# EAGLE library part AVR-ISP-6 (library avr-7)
AVR ISP-6 Serial Programming Header

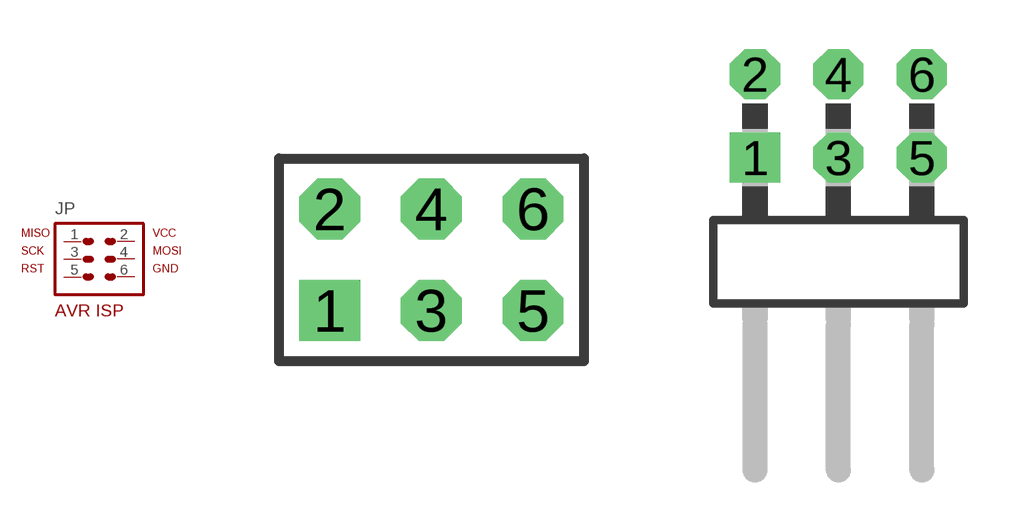
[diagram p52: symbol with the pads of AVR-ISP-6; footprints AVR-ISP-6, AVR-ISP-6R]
Designator prefix JP

## AVR-ISP-6VERT  [AVR-ISP-6]
1  1  pas
2  2  pas
3  3  pas
4  4  pas
5  5  pas
6  6  pas

## AVR-ISP-6HORZ  [AVR-ISP-6R]
Pads as for AVR-ISP-6

## Footprint AVR-ISP-6 (pad centres in mm)
PIN HEADER JTAG 6 Pin, 0.1" Straight
drill 1.016 square: 1 -2.54,-1.27
drill 1.016 octagon: 2 -2.54,1.27; 3 0,-1.27; 4 0,1.27; 5 2.54,-1.27; 6 2.54,1.27

## Footprint AVR-ISP-6R (pad centres in mm)
PIN HEADER AVR ISP 6 Pin, 0.1" Right Angle
drill 1.016 square: 1 -2.54,-1.27
drill 1.016 octagon: 2 -2.54,1.27; 3 0,-1.27; 4 0,1.27; 5 2.54,-1.27; 6 2.54,1.27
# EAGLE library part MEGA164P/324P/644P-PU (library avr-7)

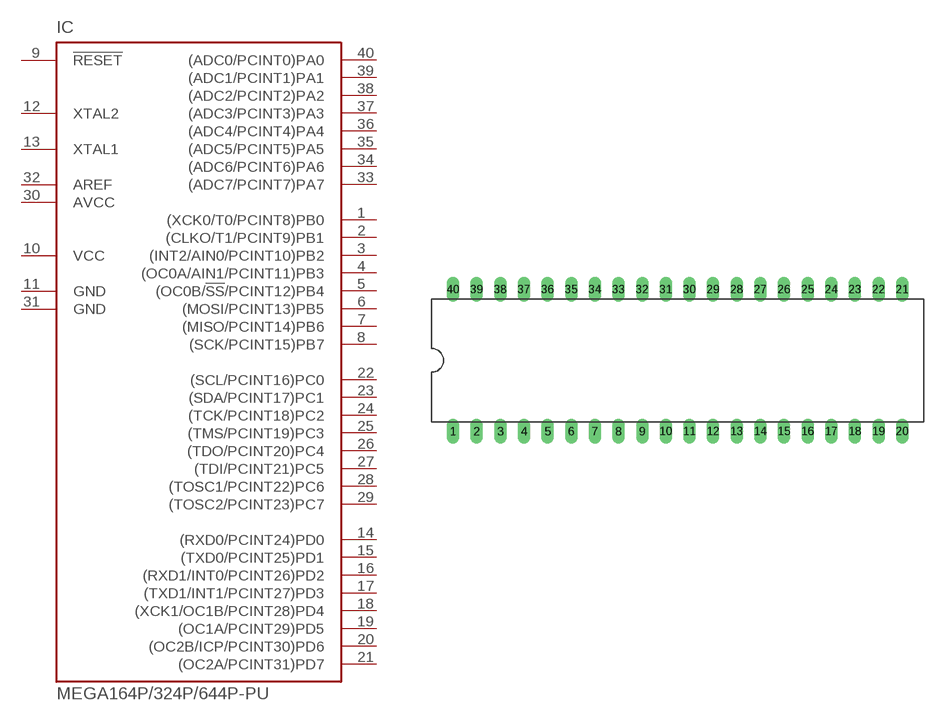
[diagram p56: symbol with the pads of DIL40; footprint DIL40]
Designator prefix IC

## MEGA164P/324P/644P-PU  [DIL40]
1  (XCK0/T0/PCINT8)PB0
2  (CLKO/T1/PCINT9)PB1
3  (INT2/AIN0/PCINT10)PB2
4  (OC0A/AIN1/PCINT11)PB3
5  (OC0B/!SS!/PCINT12)PB4
6  (MOSI/PCINT13)PB5
7  (MISO/PCINT14)PB6
8  (SCK/PCINT15)PB7
9  !RESET  in
10  VCC  pwr
11  GND  pwr
12  XTAL2  out
13  XTAL1  in
14  (RXD0/PCINT24)PD0
15  (TXD0/PCINT25)PD1
16  (RXD1/INT0/PCINT26)PD2
17  (TXD1/INT1/PCINT27)PD3
18  (XCK1/OC1B/PCINT28)PD4
19  (OC1A/PCINT29)PD5
20  (OC2B/ICP/PCINT30)PD6
21  (OC2A/PCINT31)PD7
22  (SCL/PCINT16)PC0
23  (SDA/PCINT17)PC1
24  (TCK/PCINT18)PC2
25  (TMS/PCINT19)PC3
26  (TDO/PCINT20)PC4
27  (TDI/PCINT21)PC5
28  (TOSC1/PCINT22)PC6
29  (TOSC2/PCINT23)PC7
30  AVCC  pwr
31  GND  pwr
32  AREF  pwr
33  (ADC7/PCINT7)PA7
34  (ADC6/PCINT6)PA6
35  (ADC5/PCINT5)PA5
36  (ADC4/PCINT4)PA4
37  (ADC3/PCINT3)PA3
38  (ADC2/PCINT2)PA2
39  (ADC1/PCINT1)PA1
40  (ADC0/PCINT0)PA0

## Footprint DIL40 (pad centres in mm)
Dual In Line
drill 0.813 long: 1 -24.13,-7.62; 2 -21.59,-7.62; 3 -19.05,-7.62; 4 -16.51,-7.62; 5 -13.97,-7.62; 6 -11.43,-7.62; 7 -8.89,-7.62; 8 -6.35,-7.62; 9 -3.81,-7.62; 10 -1.27,-7.62; 11 1.27,-7.62; 12 3.81,-7.62; 13 6.35,-7.62; 14 8.89,-7.62; 15 11.43,-7.62; 16 13.97,-7.62; 17 16.51,-7.62; 18 19.05,-7.62; 19 21.59,-7.62; 20 24.13,-7.62; 21 24.13,7.62; 22 21.59,7.62; 23 19.05,7.62; 24 16.51,7.62; 25 13.97,7.62; 26 11.43,7.62; 27 8.89,7.62; 28 6.35,7.62; 29 3.81,7.62; 30 1.27,7.62; 31 -1.27,7.62; 32 -3.81,7.62; 33 -6.35,7.62; 34 -8.89,7.62; 35 -11.43,7.62; 36 -13.97,7.62; 37 -16.51,7.62; 38 -19.05,7.62; 39 -21.59,7.62; 40 -24.13,7.62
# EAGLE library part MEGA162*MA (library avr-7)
Atmel Mega162 TQFP and MLF packages

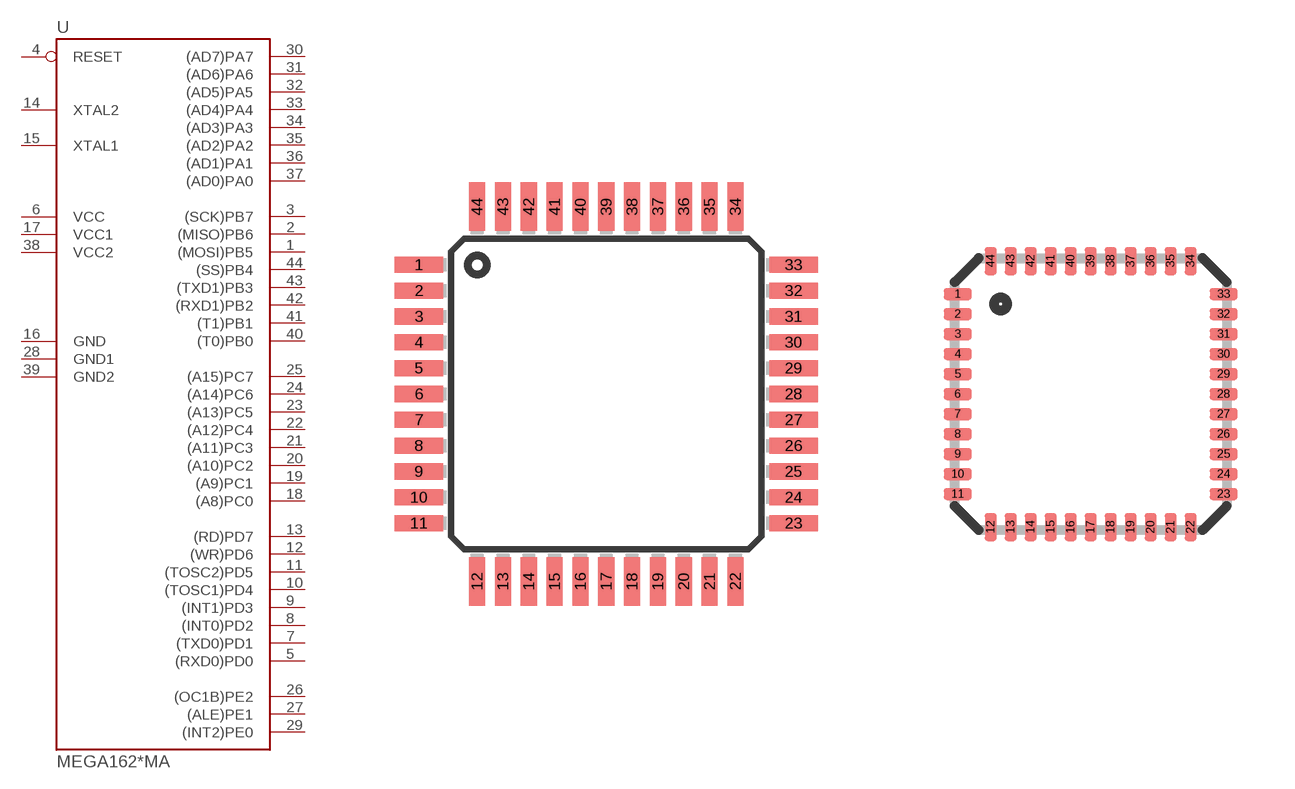
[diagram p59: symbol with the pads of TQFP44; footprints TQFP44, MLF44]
Designator prefix -

## MEGA162MA*A*  [TQFP44]
1  (MOSI)PB5
2  (MISO)PB6
3  (SCK)PB7
4  RESET  in
5  (RXD0)PD0
6  VCC  pwr
7  (TXD0)PD1
8  (INT0)PD2
9  (INT1)PD3
10  (TOSC1)PD4
11  (TOSC2)PD5
12  (WR)PD6
13  (RD)PD7
14  XTAL2  in
15  XTAL1  in
16  GND  pwr
17  VCC1  pwr
18  (A8)PC0
19  (A9)PC1
20  (A10)PC2
21  (A11)PC3
22  (A12)PC4
23  (A13)PC5
24  (A14)PC6
25  (A15)PC7
26  (OC1B)PE2
27  (ALE)PE1
28  GND1  pwr
29  (INT2)PE0
30  (AD7)PA7
31  (AD6)PA6
32  (AD5)PA5
33  (AD4)PA4
34  (AD3)PA3
35  (AD2)PA2
36  (AD1)PA1
37  (AD0)PA0
38  VCC2  pwr
39  GND2  pwr
40  (T0)PB0
41  (T1)PB1
42  (RXD1)PB2
43  (TXD1)PB3
44  (SS)PB4

## MEGA162MA*M*  [MLF44]
Pads as for TQFP44

## Footprint TQFP44 (pad centres in mm)
Thin Plasic Quad Flat Package
smd 1.5 x 0.5: 1 -5.8,4; 2 -5.8,3.2; 3 -5.8,2.4; 4 -5.8,1.6; 5 -5.8,0.8; 6 -5.8,0; 7 -5.8,-0.8; 8 -5.8,-1.6; 9 -5.8,-2.4; 10 -5.8,-3.2; 11 -5.8,-4; 23 5.8,-4; 24 5.8,-3.2; 25 5.8,-2.4; 26 5.8,-1.6; 27 5.8,-0.8; 28 5.8,0; 29 5.8,0.8; 30 5.8,1.6; 31 5.8,2.4; 32 5.8,3.2; 33 5.8,4
smd 0.5 x 1.5: 12 -4,-5.8; 13 -3.2,-5.8; 14 -2.4,-5.8; 15 -1.6,-5.8; 16 -0.8,-5.8; 17 0,-5.8; 18 0.8,-5.8; 19 1.6,-5.8; 20 2.4,-5.8; 21 3.2,-5.8; 22 4,-5.8; 34 4,5.8; 35 3.2,5.8; 36 2.4,5.8; 37 1.6,5.8; 38 0.8,5.8; 39 0,5.8; 40 -0.8,5.8; 41 -1.6,5.8; 42 -2.4,5.8; 43 -3.2,5.8; 44 -4,5.8

## Footprint MLF44 (pad centres in mm)
44M1 Micro Lead Frame package (MLF)
smd 0.7 x 0.3: 1 -3.325,2.5; 2 -3.325,2; 3 -3.325,1.5; 4 -3.325,1; 5 -3.325,0.5; 6 -3.325,0; 7 -3.325,-0.5; 8 -3.325,-1; 9 -3.325,-1.5; 10 -3.325,-2; 11 -3.325,-2.5; 23 3.325,-2.5; 24 3.325,-2; 25 3.325,-1.5; 26 3.325,-1; 27 3.325,-0.5; 28 3.325,0; 29 3.325,0.5; 30 3.325,1; 31 3.325,1.5; 32 3.325,2; 33 3.325,2.5
smd 0.3 x 0.7: 12 -2.5,-3.325; 13 -2,-3.325; 14 -1.5,-3.325; 15 -1,-3.325; 16 -0.5,-3.325; 17 0,-3.325; 18 0.5,-3.325; 19 1,-3.325; 20 1.5,-3.325; 21 2,-3.325; 22 2.5,-3.325; 34 2.5,3.325; 35 2,3.325; 36 1.5,3.325; 37 1,3.325; 38 0.5,3.325; 39 0,3.325; 40 -0.5,3.325; 41 -1,3.325; 42 -1.5,3.325; 43 -2,3.325; 44 -2.5,3.325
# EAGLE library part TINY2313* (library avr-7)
Atmel Tiny2313 2K Flash, 128 bytes EEPROM, 128 bytes RAM

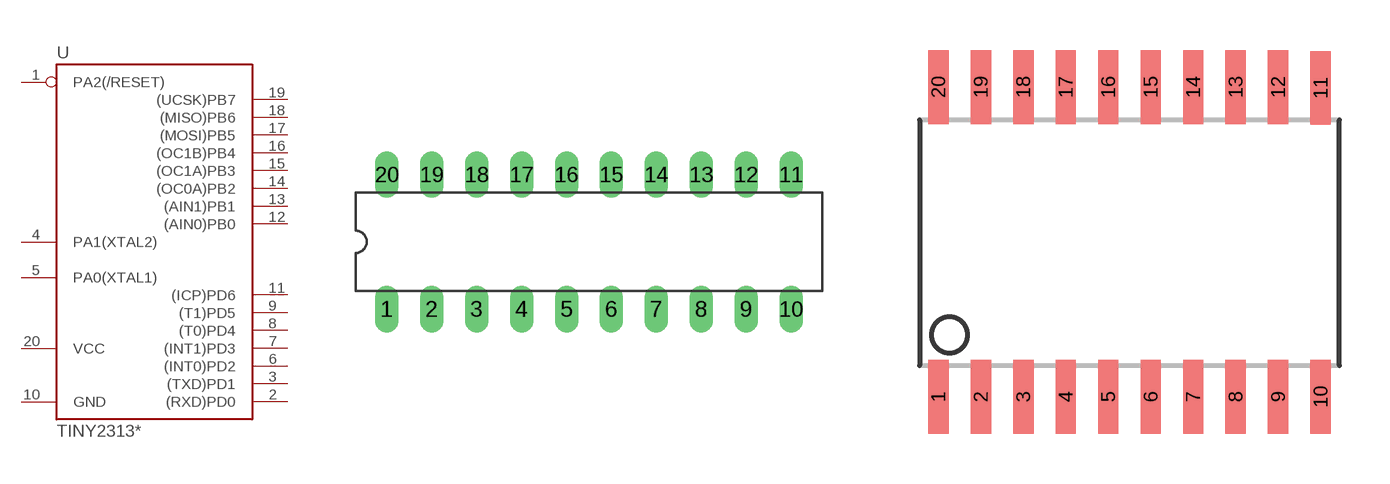
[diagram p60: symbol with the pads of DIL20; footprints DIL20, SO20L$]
Designator prefix -

## TINY2313-*P*  [DIL20]
1  PA2(/RESET)  in
2  (RXD)PD0
3  (TXD)PD1
4  PA1(XTAL2)
5  PA0(XTAL1)
6  (INT0)PD2
7  (INT1)PD3
8  (T0)PD4
9  (T1)PD5
10  GND  pwr
11  (ICP)PD6
12  (AIN0)PB0
13  (AIN1)PB1
14  (OC0A)PB2
15  (OC1A)PB3
16  (OC1B)PB4
17  (MOSI)PB5
18  (MISO)PB6
19  (UCSK)PB7
20  VCC  pwr

## TINY2313-*S*  [SO20L$]
Pads as for DIL20

## TINY2313-*M*  [MLF20]
P$1  (TXD)PD1
P$2  PA1(XTAL2)
P$3  PA0(XTAL1)
P$4  (INT0)PD2
P$5  (INT1)PD3
P$6  (T0)PD4
P$7  (T1)PD5
P$8  GND  pwr
P$9  (ICP)PD6
P$10  (AIN0)PB0
P$11  (AIN1)PB1
P$12  (OC0A)PB2
P$13  (OC1A)PB3
P$14  (OC1B)PB4
P$15  (MOSI)PB5
P$16  (MISO)PB6
P$17  (UCSK)PB7
P$18  VCC  pwr
P$19  PA2(/RESET)  in
P$20  (RXD)PD0

## Footprint DIL20 (pad centres in mm)
Dual In Line
drill 0.813 long: 1 -11.43,-3.81; 2 -8.89,-3.81; 3 -6.35,-3.81; 4 -3.81,-3.81; 5 -1.27,-3.81; 6 1.27,-3.81; 7 3.81,-3.81; 8 6.35,-3.81; 9 8.89,-3.81; 10 11.43,-3.81; 11 11.43,3.81; 12 8.89,3.81; 13 6.35,3.81; 14 3.81,3.81; 15 1.27,3.81; 16 -1.27,3.81; 17 -3.81,3.81; 18 -6.35,3.81; 19 -8.89,3.81; 20 -11.43,3.81

## Footprint SO20L$ (pad centres in mm)
Small Outline Package, large
smd 0.61 x 2.21: 1 -5.715,-4.636; 2 -4.445,-4.636; 3 -3.175,-4.636; 4 -1.905,-4.636; 5 -0.635,-4.636; 6 0.635,-4.636; 7 1.905,-4.636; 8 3.175,-4.636; 9 4.445,-4.636; 10 5.715,-4.636; 11 5.715,4.61; 12 4.445,4.636; 13 3.175,4.636; 14 1.905,4.636; 15 0.635,4.636; 16 -0.635,4.636; 17 -1.905,4.636; 18 -3.175,4.636; 19 -4.445,4.636; 20 -5.715,4.636

## Footprint MLF20 (pad centres in mm)
HP-VFQFP-N20 Micro Lead Frame package (MLF)
smd 0.8 x 0.23: P$1 -2,1; P$2 -2,0.5; P$3 -2,0; P$4 -2,-0.5; P$5 -2,-1; P$11 2,-1; P$12 2,-0.5; P$13 2,0; P$14 2,0.5; P$15 2,1
smd 0.23 x 0.8: P$6 -1,-2; P$7 -0.5,-2; P$8 0,-2; P$9 0.5,-2; P$10 1,-2; P$16 1,2; P$17 0.5,2; P$18 0,2; P$19 -0.5,2; P$20 -1,2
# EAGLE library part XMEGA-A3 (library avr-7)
Atmel XMega A3 series processor

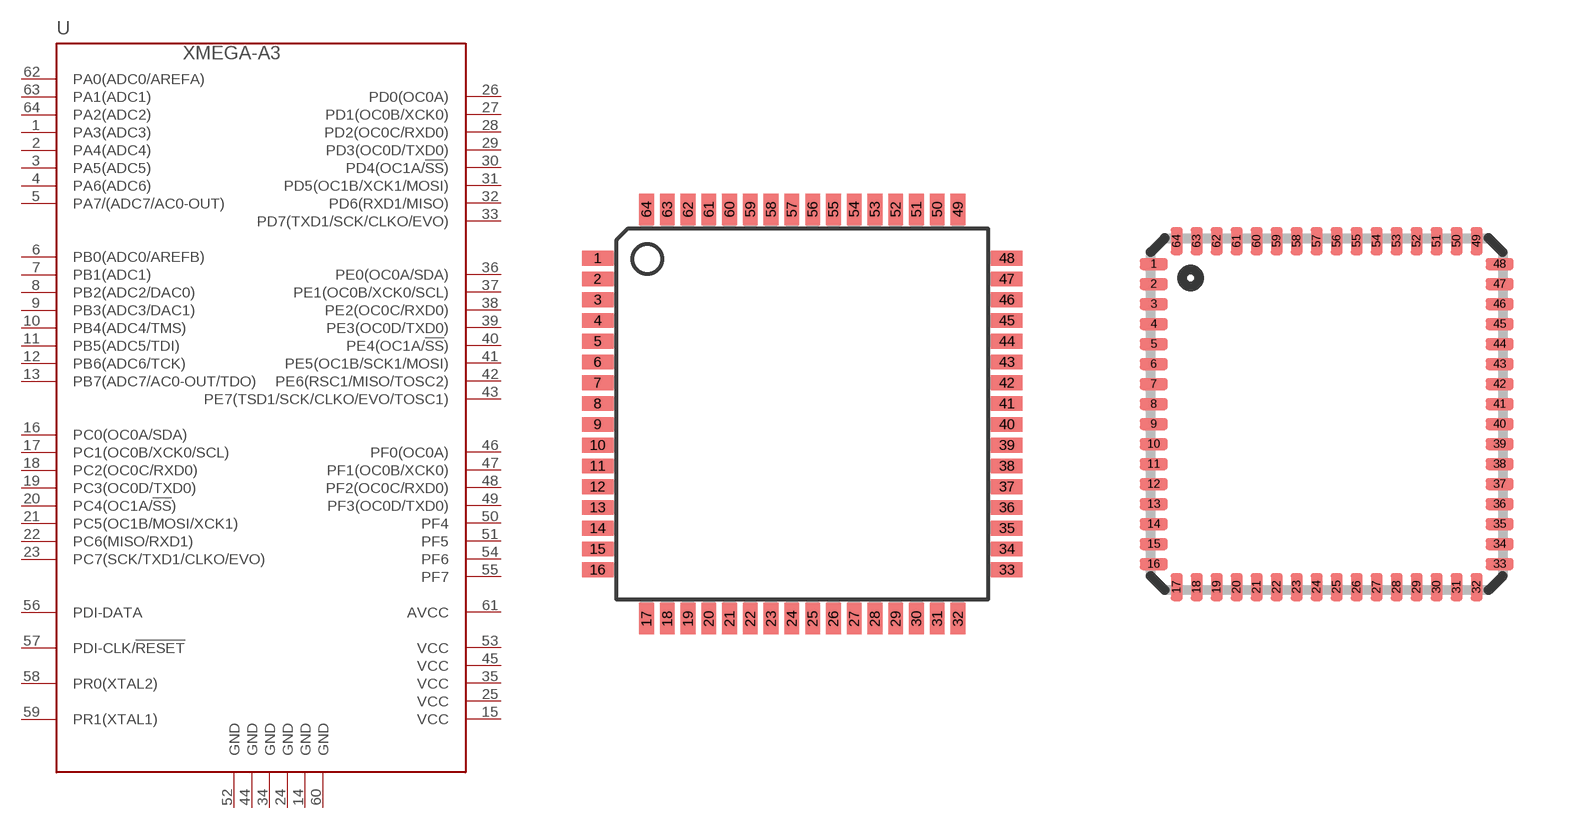
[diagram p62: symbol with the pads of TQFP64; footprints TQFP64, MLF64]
Designator prefix -

## XMEGA-A3TQFP  [TQFP64]
1  PA3(ADC3)
2  PA4(ADC4)
3  PA5(ADC5)
4  PA6(ADC6)
5  PA7/(ADC7/AC0-OUT)
6  PB0(ADC0/AREFB)
7  PB1(ADC1)
8  PB2(ADC2/DAC0)
9  PB3(ADC3/DAC1)
10  PB4(ADC4/TMS)
11  PB5(ADC5/TDI)
12  PB6(ADC6/TCK)
13  PB7(ADC7/AC0-OUT/TDO)
14  GND  pwr
15  VCC  pwr
16  PC0(OC0A/SDA)
17  PC1(OC0B/XCK0/SCL)
18  PC2(OC0C/RXD0)
19  PC3(OC0D/TXD0)
20  PC4(OC1A/!SS!)
21  PC5(OC1B/MOSI/XCK1)
22  PC6(MISO/RXD1)
23  PC7(SCK/TXD1/CLKO/EVO)
24  GND  pwr
25  VCC  pwr
26  PD0(OC0A)
27  PD1(OC0B/XCK0)
28  PD2(OC0C/RXD0)
29  PD3(OC0D/TXD0)
30  PD4(OC1A/!SS!)
31  PD5(OC1B/XCK1/MOSI)
32  PD6(RXD1/MISO)
33  PD7(TXD1/SCK/CLKO/EVO)
34  GND  pwr
35  VCC  pwr
36  PE0(OC0A/SDA)
37  PE1(OC0B/XCK0/SCL)
38  PE2(OC0C/RXD0)
39  PE3(OC0D/TXD0)
40  PE4(OC1A/!SS!)
41  PE5(OC1B/SCK1/MOSI)
42  PE6(RSC1/MISO/TOSC2)
43  PE7(TSD1/SCK/CLKO/EVO/TOSC1)
44  GND  pwr
45  VCC  pwr
46  PF0(OC0A)
47  PF1(OC0B/XCK0)
48  PF2(OC0C/RXD0)
49  PF3(OC0D/TXD0)
50  PF4
51  PF5
52  GND  pwr
53  VCC  pwr
54  PF6
55  PF7
56  PDI-DATA
57  PDI-CLK/!RESET  in
58  PR0(XTAL2)
59  PR1(XTAL1)
60  GND  pwr
61  AVCC  pwr
62  PA0(ADC0/AREFA)
63  PA1(ADC1)
64  PA2(ADC2)

## XMEGA-A3MLF  [MLF64]
Pads as for TQFP64

## Footprint TQFP64 (pad centres in mm)
Thin Plasic Quad Flat Package
smd 1.194 x 0.559: 1 -7.76,5.905; 2 -7.76,5.118; 3 -7.76,4.331; 4 -7.76,3.543; 5 -7.76,2.756; 6 -7.76,1.968; 7 -7.76,1.181; 8 -7.76,0.394; 9 -7.76,-0.394; 10 -7.76,-1.181; 11 -7.76,-1.968; 12 -7.76,-2.756; 13 -7.76,-3.543; 14 -7.76,-4.331; 15 -7.76,-5.118; 16 -7.76,-5.905; 33 7.76,-5.905; 34 7.76,-5.118; 35 7.76,-4.331; 36 7.76,-3.543; 37 7.76,-2.756; 38 7.76,-1.968; 39 7.76,-1.181; 40 7.76,-0.394; 41 7.76,0.394; 42 7.76,1.181; 43 7.76,1.968; 44 7.76,2.756; 45 7.76,3.543; 46 7.76,4.331; 47 7.76,5.118; 48 7.76,5.905
smd 0.559 x 1.194: 17 -5.905,-7.76; 18 -5.118,-7.76; 19 -4.331,-7.76; 20 -3.543,-7.76; 21 -2.756,-7.76; 22 -1.968,-7.76; 23 -1.181,-7.76; 24 -0.394,-7.76; 25 0.394,-7.76; 26 1.181,-7.76; 27 1.968,-7.76; 28 2.756,-7.76; 29 3.543,-7.76; 30 4.331,-7.76; 31 5.118,-7.76; 32 5.905,-7.76; 49 5.905,7.76; 50 5.118,7.76; 51 4.331,7.76; 52 3.543,7.76; 53 2.756,7.76; 54 1.968,7.76; 55 1.181,7.76; 56 0.394,7.76; 57 -0.394,7.76; 58 -1.181,7.76; 59 -1.968,7.76; 60 -2.756,7.76; 61 -3.543,7.76; 62 -4.331,7.76; 63 -5.118,7.76; 64 -5.905,7.76

## Footprint MLF64 (pad centres in mm)
64M1 Micro Lead Frame package (MLF)
smd 0.7 x 0.3: 1 -4.325,3.75; 2 -4.325,3.25; 3 -4.325,2.75; 4 -4.325,2.25; 5 -4.325,1.75; 6 -4.325,1.25; 7 -4.325,0.75; 8 -4.325,0.25; 9 -4.325,-0.25; 10 -4.325,-0.75; 11 -4.325,-1.25; 12 -4.325,-1.75; 13 -4.325,-2.25; 14 -4.325,-2.75; 15 -4.325,-3.25; 16 -4.325,-3.75; 33 4.325,-3.75; 34 4.325,-3.25; 35 4.325,-2.75; 36 4.325,-2.25; 37 4.325,-1.75; 38 4.325,-1.25; 39 4.325,-0.75; 40 4.325,-0.25; 41 4.325,0.25; 42 4.325,0.75; 43 4.325,1.25; 44 4.325,1.75; 45 4.325,2.25; 46 4.325,2.75; 47 4.325,3.25; 48 4.325,3.75
smd 0.3 x 0.7: 17 -3.75,-4.325; 18 -3.25,-4.325; 19 -2.75,-4.325; 20 -2.25,-4.325; 21 -1.75,-4.325; 22 -1.25,-4.325; 23 -0.75,-4.325; 24 -0.25,-4.325; 25 0.25,-4.325; 26 0.75,-4.325; 27 1.25,-4.325; 28 1.75,-4.325; 29 2.25,-4.325; 30 2.75,-4.325; 31 3.25,-4.325; 32 3.75,-4.325; 49 3.75,4.325; 50 3.25,4.325; 51 2.75,4.325; 52 2.25,4.325; 53 1.75,4.325; 54 1.25,4.325; 55 0.75,4.325; 56 0.25,4.325; 57 -0.25,4.325; 58 -0.75,4.325; 59 -1.25,4.325; 60 -1.75,4.325; 61 -2.25,4.325; 62 -2.75,4.325; 63 -3.25,4.325; 64 -3.75,4.325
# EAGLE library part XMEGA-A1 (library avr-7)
Atmel XMega A1 Series processor

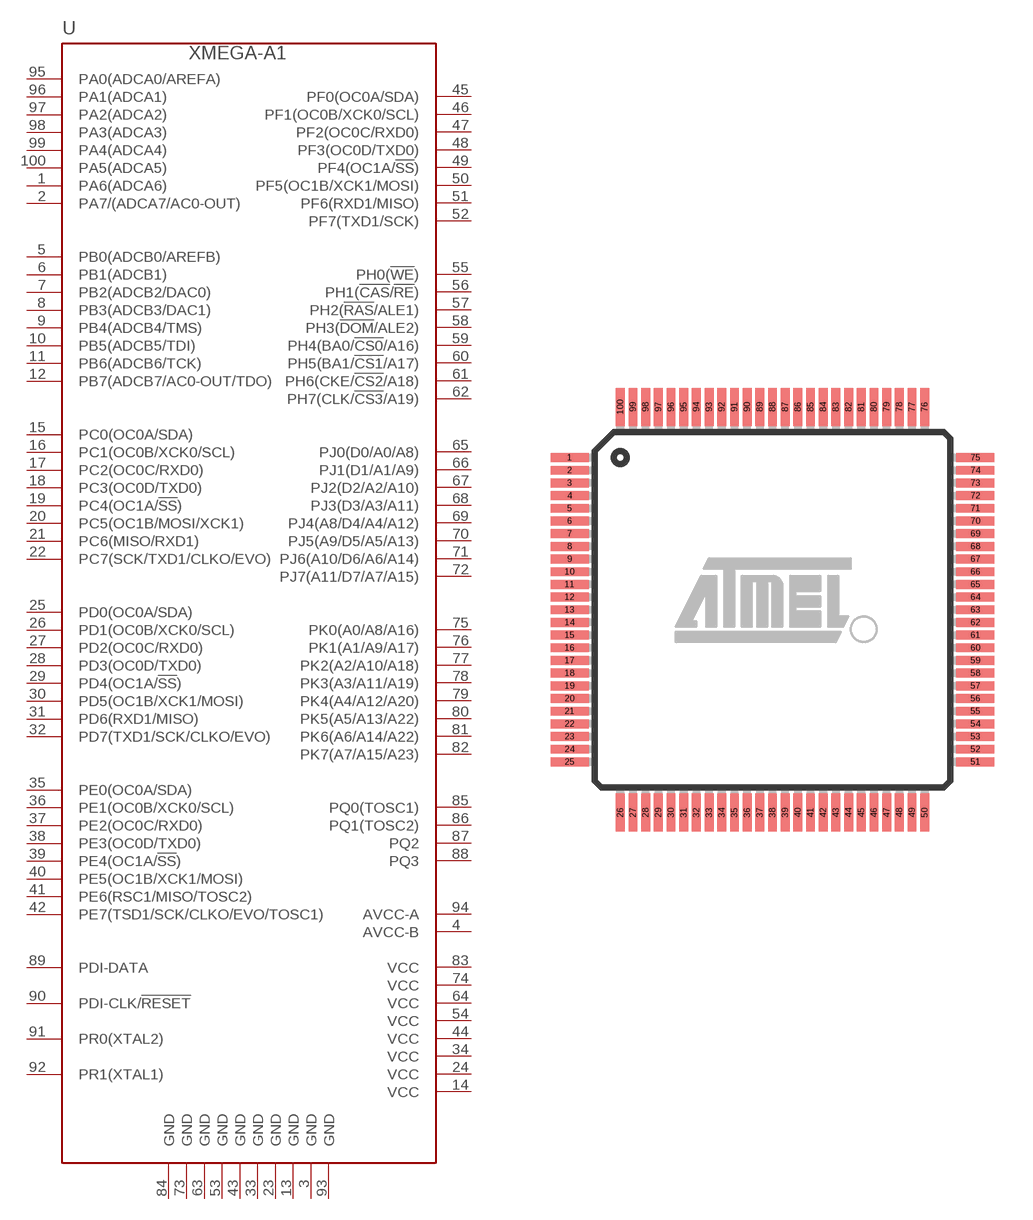
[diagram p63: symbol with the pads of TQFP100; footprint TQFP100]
Designator prefix -

## XMEGA-A1TQFP  [TQFP100]
1  PA6(ADCA6)
2  PA7/(ADCA7/AC0-OUT)
3  GND  pwr
4  AVCC-B  pwr
5  PB0(ADCB0/AREFB)
6  PB1(ADCB1)
7  PB2(ADCB2/DAC0)
8  PB3(ADCB3/DAC1)
9  PB4(ADCB4/TMS)
10  PB5(ADCB5/TDI)
11  PB6(ADCB6/TCK)
12  PB7(ADCB7/AC0-OUT/TDO)
13  GND  pwr
14  VCC  pwr
15  PC0(OC0A/SDA)
16  PC1(OC0B/XCK0/SCL)
17  PC2(OC0C/RXD0)
18  PC3(OC0D/TXD0)
19  PC4(OC1A/!SS!)
20  PC5(OC1B/MOSI/XCK1)
21  PC6(MISO/RXD1)
22  PC7(SCK/TXD1/CLKO/EVO)
23  GND  pwr
24  VCC  pwr
25  PD0(OC0A/SDA)
26  PD1(OC0B/XCK0/SCL)
27  PD2(OC0C/RXD0)
28  PD3(OC0D/TXD0)
29  PD4(OC1A/!SS!)
30  PD5(OC1B/XCK1/MOSI)
31  PD6(RXD1/MISO)
32  PD7(TXD1/SCK/CLKO/EVO)
33  GND  pwr
34  VCC  pwr
35  PE0(OC0A/SDA)
36  PE1(OC0B/XCK0/SCL)
37  PE2(OC0C/RXD0)
38  PE3(OC0D/TXD0)
39  PE4(OC1A/!SS!)
40  PE5(OC1B/XCK1/MOSI)
41  PE6(RSC1/MISO/TOSC2)
42  PE7(TSD1/SCK/CLKO/EVO/TOSC1)
43  GND  pwr
44  VCC  pwr
45  PF0(OC0A/SDA)
46  PF1(OC0B/XCK0/SCL)
47  PF2(OC0C/RXD0)
48  PF3(OC0D/TXD0)
49  PF4(OC1A/!SS!)
50  PF5(OC1B/XCK1/MOSI)
51  PF6(RXD1/MISO)
52  PF7(TXD1/SCK)
53  GND  pwr
54  VCC  pwr
55  PH0(!WE!)
56  PH1(!CAS!/!RE!)
57  PH2(!RAS!/ALE1)
58  PH3(!DOM!/ALE2)
59  PH4(BA0/!CS0!/A16)
60  PH5(BA1/!CS1!/A17)
61  PH6(CKE/!CS2!/A18)
62  PH7(CLK/!CS3!/A19)
63  GND  pwr
64  VCC  pwr
65  PJ0(D0/A0/A8)
66  PJ1(D1/A1/A9)
67  PJ2(D2/A2/A10)
68  PJ3(D3/A3/A11)
69  PJ4(A8/D4/A4/A12)
70  PJ5(A9/D5/A5/A13)
71  PJ6(A10/D6/A6/A14)
72  PJ7(A11/D7/A7/A15)
73  GND  pwr
74  VCC  pwr
75  PK0(A0/A8/A16)
76  PK1(A1/A9/A17)
77  PK2(A2/A10/A18)
78  PK3(A3/A11/A19)
79  PK4(A4/A12/A20)
80  PK5(A5/A13/A22)
81  PK6(A6/A14/A22)
82  PK7(A7/A15/A23)
83  VCC  pwr
84  GND  pwr
85  PQ0(TOSC1)
86  PQ1(TOSC2)
87  PQ2
88  PQ3
89  PDI-DATA
90  PDI-CLK/!RESET  in
91  PR0(XTAL2)
92  PR1(XTAL1)
93  GND  pwr
94  AVCC-A  pwr
95  PA0(ADCA0/AREFA)
96  PA1(ADCA1)
97  PA2(ADCA2)
98  PA3(ADCA3)
99  PA4(ADCA4)
100  PA5(ADCA5)

## Footprint TQFP100 (pad centres in mm)
100-lead Thin Quad Flat Pack Package Outline
smd 1.5 x 0.35: 1 -8,6; 2 -8,5.5; 3 -8,5; 4 -8,4.5; 5 -8,4; 6 -8,3.5; 7 -8,3; 8 -8,2.5; 9 -8,2; 10 -8,1.5; 11 -8,1; 12 -8,0.5; 13 -8,0; 14 -8,-0.5; 15 -8,-1; 16 -8,-1.5; 17 -8,-2; 18 -8,-2.5; 19 -8,-3; 20 -8,-3.5; 21 -8,-4; 22 -8,-4.5; 23 -8,-5; 24 -8,-5.5; 25 -8,-6; 51 8,-6; 52 8,-5.5; 53 8,-5; 54 8,-4.5; 55 8,-4; 56 8,-3.5; 57 8,-3; 58 8,-2.5; 59 8,-2; 60 8,-1.5; 61 8,-1; 62 8,-0.5; 63 8,0; 64 8,0.5; 65 8,1; 66 8,1.5; 67 8,2; 68 8,2.5; 69 8,3; 70 8,3.5; 71 8,4; 72 8,4.5; 73 8,5; 74 8,5.5; 75 8,6
smd 0.35 x 1.5: 26 -6,-8; 27 -5.5,-8; 28 -5,-8; 29 -4.5,-8; 30 -4,-8; 31 -3.5,-8; 32 -3,-8; 33 -2.5,-8; 34 -2,-8; 35 -1.5,-8; 36 -1,-8; 37 -0.5,-8; 38 0,-8; 39 0.5,-8; 40 1,-8; 41 1.5,-8; 42 2,-8; 43 2.5,-8; 44 3,-8; 45 3.5,-8; 46 4,-8; 47 4.5,-8; 48 5,-8; 49 5.5,-8; 50 6,-8; 76 6,8; 77 5.5,8; 78 5,8; 79 4.5,8; 80 4,8; 81 3.5,8; 82 3,8; 83 2.5,8; 84 2,8; 85 1.5,8; 86 1,8; 87 0.5,8; 88 0,8; 89 -0.5,8; 90 -1,8; 91 -1.5,8; 92 -2,8; 93 -2.5,8; 94 -3,8; 95 -3.5,8; 96 -4,8; 97 -4.5,8; 98 -5,8; 99 -5.5,8; 100 -6,8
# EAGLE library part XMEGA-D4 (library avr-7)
Atmel AVR XMega D4 series processor

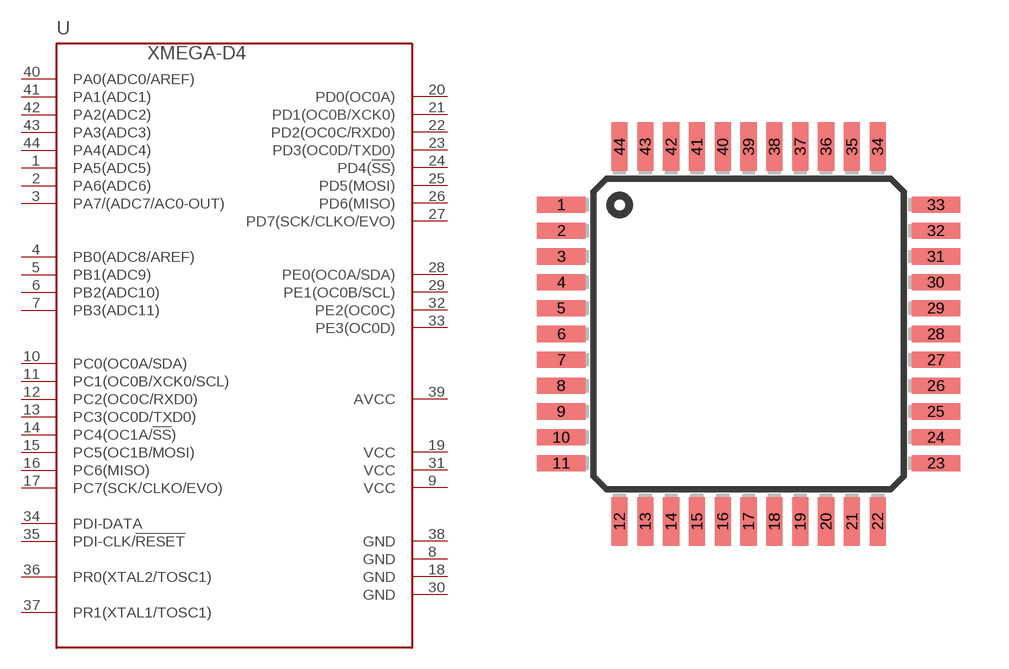
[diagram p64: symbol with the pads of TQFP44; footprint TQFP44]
Designator prefix -

## XMEGA-D4TQFP  [TQFP44]
1  PA5(ADC5)
2  PA6(ADC6)
3  PA7/(ADC7/AC0-OUT)
4  PB0(ADC8/AREF)
5  PB1(ADC9)
6  PB2(ADC10)
7  PB3(ADC11)
8  GND  pwr
9  VCC  pwr
10  PC0(OC0A/SDA)
11  PC1(OC0B/XCK0/SCL)
12  PC2(OC0C/RXD0)
13  PC3(OC0D/TXD0)
14  PC4(OC1A/!SS!)
15  PC5(OC1B/MOSI)
16  PC6(MISO)
17  PC7(SCK/CLKO/EVO)
18  GND  pwr
19  VCC  pwr
20  PD0(OC0A)
21  PD1(OC0B/XCK0)
22  PD2(OC0C/RXD0)
23  PD3(OC0D/TXD0)
24  PD4(!SS!)
25  PD5(MOSI)
26  PD6(MISO)
27  PD7(SCK/CLKO/EVO)
28  PE0(OC0A/SDA)
29  PE1(OC0B/SCL)
30  GND  pwr
31  VCC  pwr
32  PE2(OC0C)
33  PE3(OC0D)
34  PDI-DATA
35  PDI-CLK/!RESET  in
36  PR0(XTAL2/TOSC1)
37  PR1(XTAL1/TOSC1)
38  GND  pwr
39  AVCC  pwr
40  PA0(ADC0/AREF)
41  PA1(ADC1)
42  PA2(ADC2)
43  PA3(ADC3)
44  PA4(ADC4)

## Footprint TQFP44 (pad centres in mm)
Thin Plasic Quad Flat Package
smd 1.5 x 0.5: 1 -5.8,4; 2 -5.8,3.2; 3 -5.8,2.4; 4 -5.8,1.6; 5 -5.8,0.8; 6 -5.8,0; 7 -5.8,-0.8; 8 -5.8,-1.6; 9 -5.8,-2.4; 10 -5.8,-3.2; 11 -5.8,-4; 23 5.8,-4; 24 5.8,-3.2; 25 5.8,-2.4; 26 5.8,-1.6; 27 5.8,-0.8; 28 5.8,0; 29 5.8,0.8; 30 5.8,1.6; 31 5.8,2.4; 32 5.8,3.2; 33 5.8,4
smd 0.5 x 1.5: 12 -4,-5.8; 13 -3.2,-5.8; 14 -2.4,-5.8; 15 -1.6,-5.8; 16 -0.8,-5.8; 17 0,-5.8; 18 0.8,-5.8; 19 1.6,-5.8; 20 2.4,-5.8; 21 3.2,-5.8; 22 4,-5.8; 34 4,5.8; 35 3.2,5.8; 36 2.4,5.8; 37 1.6,5.8; 38 0.8,5.8; 39 0,5.8; 40 -0.8,5.8; 41 -1.6,5.8; 42 -2.4,5.8; 43 -3.2,5.8; 44 -4,5.8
